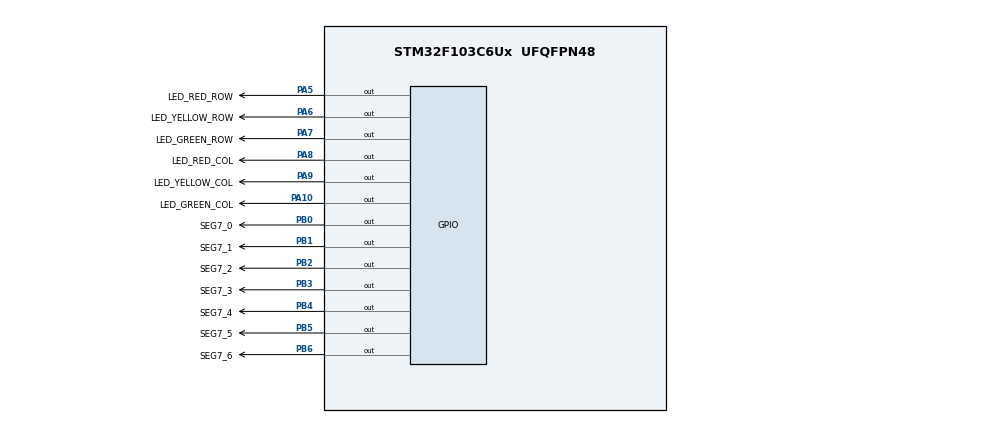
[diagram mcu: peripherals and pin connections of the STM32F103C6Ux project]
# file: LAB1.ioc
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Mcu.Family=STM32F1
Mcu.Name=STM32F103C6Ux
Mcu.Package=UFQFPN48
NVIC.PriorityGroup=NVIC_PRIORITYGROUP_4
PA10.GPIO_Label=LED_GREEN_COL
PA10.Signal=GPIO_Output
PA5.GPIO_Label=LED_RED_ROW
PA5.Signal=GPIO_Output
PA6.GPIO_Label=LED_YELLOW_ROW
PA6.Signal=GPIO_Output
PA7.GPIO_Label=LED_GREEN_ROW
PA7.Signal=GPIO_Output
PA8.GPIO_Label=LED_RED_COL
PA8.Signal=GPIO_Output
PA9.GPIO_Label=LED_YELLOW_COL
PA9.Signal=GPIO_Output
PB0.GPIO_Label=SEG7_0
PB0.Signal=GPIO_Output
PB1.GPIO_Label=SEG7_1
PB1.Signal=GPIO_Output
PB2.GPIO_Label=SEG7_2
PB2.Signal=GPIO_Output
PB3.GPIO_Label=SEG7_3
PB3.Signal=GPIO_Output
PB4.GPIO_Label=SEG7_4
PB4.Signal=GPIO_Output
PB5.GPIO_Label=SEG7_5
PB5.Signal=GPIO_Output
PB6.GPIO_Label=SEG7_6
PB6.Signal=GPIO_Output
ProjectManager.HeapSize=0x200
ProjectManager.StackSize=0x400
ProjectManager.TargetToolchain=STM32CubeIDE
RCC.APB1Freq_Value=8000000
RCC.APB2Freq_Value=8000000
VP_SYS_VS_ND.Mode=No_Debug
board=custom

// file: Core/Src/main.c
/* USER CODE BEGIN Header */
/**
  ******************************************************************************
  * @file           : main.c
  * @brief          : Main program body
  ******************************************************************************
  * @attention
  *
  * <h2><center>&copy; Copyright (c) 2023 STMicroelectronics.
  * All rights reserved.</center></h2>
  *
  * This software component is licensed by ST under BSD 3-Clause license,
  * the "License"; You may not use this file except in compliance with the
  * License. You may obtain a copy of the License at:
  *                        opensource.org/licenses/BSD-3-Clause
  *
  ******************************************************************************
  */
/* USER CODE END Header */
#include "main.h"

void SystemClock_Config(void);
static void MX_GPIO_Init(void);

uint16_t Clock[12] = {GPIO_PIN_4, GPIO_PIN_5, GPIO_PIN_6, GPIO_PIN_7, GPIO_PIN_8, GPIO_PIN_9, GPIO_PIN_10, GPIO_PIN_11, GPIO_PIN_12, GPIO_PIN_13, GPIO_PIN_14, GPIO_PIN_15};
int main(void)
{

  /* MCU Configuration--------------------------------------------------------*/

  /* Reset of all peripherals, Initializes the Flash interface and the Systick. */
  HAL_Init();

  /* Configure the system clock */
  SystemClock_Config();

  /* Initialize all configured peripherals */
  MX_GPIO_Init();

  /* Infinite loop */
  /* USER CODE BEGIN WHILE */
  int time=0;
  while (1)
  {
    /* USER CODE END WHILE */
	  if (time >=12) time =0;
	  HAL_GPIO_TogglePin(GPIOA, Clock[time]);
	  time++;
	  HAL_Delay(1000);
  }
}

void SystemClock_Config(void)
{
  RCC_OscInitTypeDef RCC_OscInitStruct = {0};
  RCC_ClkInitTypeDef RCC_ClkInitStruct = {0};

  /** Initializes the RCC Oscillators according to the specified parameters
  * in the RCC_OscInitTypeDef structure.
  */
  RCC_OscInitStruct.OscillatorType = RCC_OSCILLATORTYPE_HSI;
  RCC_OscInitStruct.HSIState = RCC_HSI_ON;
  RCC_OscInitStruct.HSICalibrationValue = RCC_HSICALIBRATION_DEFAULT;
  RCC_OscInitStruct.PLL.PLLState = RCC_PLL_NONE;
  if (HAL_RCC_OscConfig(&RCC_OscInitStruct) != HAL_OK)
  {
    Error_Handler();
  }
  /** Initializes the CPU, AHB and APB buses clocks
  */
  RCC_ClkInitStruct.ClockType = RCC_CLOCKTYPE_HCLK|RCC_CLOCKTYPE_SYSCLK
                              |RCC_CLOCKTYPE_PCLK1|RCC_CLOCKTYPE_PCLK2;
  RCC_ClkInitStruct.SYSCLKSource = RCC_SYSCLKSOURCE_HSI;
  RCC_ClkInitStruct.AHBCLKDivider = RCC_SYSCLK_DIV1;
  RCC_ClkInitStruct.APB1CLKDivider = RCC_HCLK_DIV1;
  RCC_ClkInitStruct.APB2CLKDivider = RCC_HCLK_DIV1;

  if (HAL_RCC_ClockConfig(&RCC_ClkInitStruct, FLASH_LATENCY_0) != HAL_OK)
  {
    Error_Handler();
  }
}

static void MX_GPIO_Init(void)
{
  GPIO_InitTypeDef GPIO_InitStruct = {0};

  /* GPIO Ports Clock Enable */
  __HAL_RCC_GPIOA_CLK_ENABLE();

  /*Configure GPIO pin Output Level */
  HAL_GPIO_WritePin(GPIOA, GPIO_PIN_4|GPIO_PIN_5|GPIO_PIN_6|GPIO_PIN_7
                          |GPIO_PIN_8|GPIO_PIN_9|GPIO_PIN_10|GPIO_PIN_11
                          |GPIO_PIN_12|GPIO_PIN_13|GPIO_PIN_14|GPIO_PIN_15, GPIO_PIN_RESET);

  /*Configure GPIO pins : PA4 PA5 PA6 PA7
                           PA8 PA9 PA10 PA11
                           PA12 PA13 PA14 PA15 */
  GPIO_InitStruct.Pin = GPIO_PIN_4|GPIO_PIN_5|GPIO_PIN_6|GPIO_PIN_7
                          |GPIO_PIN_8|GPIO_PIN_9|GPIO_PIN_10|GPIO_PIN_11
                          |GPIO_PIN_12|GPIO_PIN_13|GPIO_PIN_14|GPIO_PIN_15;
  GPIO_InitStruct.Mode = GPIO_MODE_OUTPUT_PP;
  GPIO_InitStruct.Pull = GPIO_NOPULL;
  GPIO_InitStruct.Speed = GPIO_SPEED_FREQ_LOW;
  HAL_GPIO_Init(GPIOA, &GPIO_InitStruct);

}

void Error_Handler(void)
{
  __disable_irq();
  while (1)
  {
  }
}

/************************ (C) COPYRIGHT STMicroelectronics *****END OF FILE****/
